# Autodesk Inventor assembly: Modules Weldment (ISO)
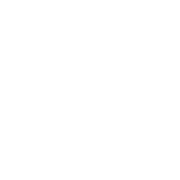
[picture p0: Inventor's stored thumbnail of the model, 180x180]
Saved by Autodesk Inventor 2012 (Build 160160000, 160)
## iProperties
Created: 2007-02
Part Number: Modules Weldment (ISO)
Document SubType Name: Weldment
Designer: Wally Jones
Weld Material: Welded Aluminum-6061
Author: Wally Jones
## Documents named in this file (1)
- C:\!Wally\!!AutoCAD Modules!!\!Inventor\Templates\Metric Templates\Modules Weldment (ISO).iam
